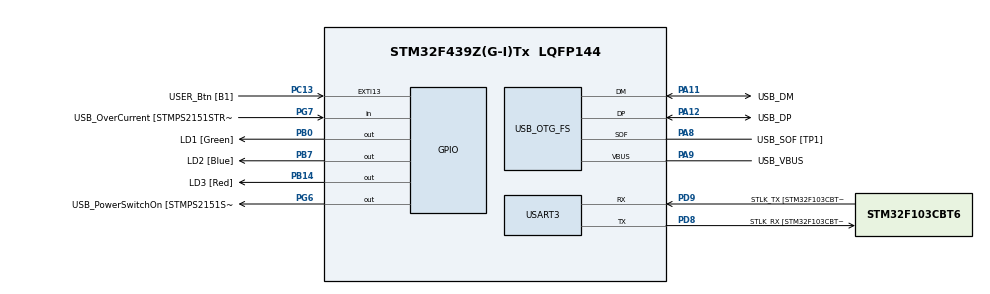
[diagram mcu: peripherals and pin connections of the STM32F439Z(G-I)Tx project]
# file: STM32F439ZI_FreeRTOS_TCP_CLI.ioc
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Mcu.Family=STM32F4
Mcu.Name=STM32F439Z(G-I)Tx
Mcu.Package=LQFP144
NVIC.PriorityGroup=NVIC_PRIORITYGROUP_4
NVIC.TIM6_DAC_IRQn=true\:15\:0\:false\:false\:true\:false\:true\:true
NVIC.TIM7_IRQn=true\:5\:0\:true\:false\:true\:true\:true\:true
NVIC.TimeBase=TIM6_DAC_IRQn
NVIC.TimeBaseIP=TIM6
PA1.GPIO_Label=RMII_REF_CLK [LAN8742A-CZ-TR_REFCLK0]
PA1.Signal=ETH_REF_CLK
PA10.GPIO_Label=USB_ID
PA10.Signal=USB_OTG_FS_ID
PA11.GPIO_Label=USB_DM
PA11.Mode=Device_Only
PA11.Signal=USB_OTG_FS_DM
PA12.GPIO_Label=USB_DP
PA12.Mode=Device_Only
PA12.Signal=USB_OTG_FS_DP
PA13.GPIO_Label=TMS
PA13.Mode=Serial_Wire
PA13.Signal=SYS_JTMS-SWDIO
PA14.GPIO_Label=TCK
PA14.Mode=Serial_Wire
PA14.Signal=SYS_JTCK-SWCLK
PA2.GPIO_Label=RMII_MDIO [LAN8742A-CZ-TR_MDIO]
PA2.Signal=ETH_MDIO
PA7.GPIO_Label=RMII_CRS_DV [LAN8742A-CZ-TR_CRS_DV]
PA7.Signal=ETH_CRS_DV
PA8.GPIO_Label=USB_SOF [TP1]
PA8.Mode=Activate_SOF_FS
PA8.Signal=USB_OTG_FS_SOF
PA9.GPIO_Label=USB_VBUS
PA9.Mode=Activate_VBUS
PA9.Signal=USB_OTG_FS_VBUS
PB0.GPIO_Label=LD1 [Green]
PB0.Signal=GPIO_Output
PB13.GPIO_Label=RMII_TXD1 [LAN8742A-CZ-TR_TXD1]
PB13.Signal=ETH_TXD1
PB14.GPIO_Label=LD3 [Red]
PB14.Signal=GPIO_Output
PB7.GPIO_Label=LD2 [Blue]
PB7.Signal=GPIO_Output
PC1.GPIO_Label=RMII_MDC [LAN8742A-CZ-TR_MDC]
PC1.Signal=ETH_MDC
PC13.GPIO_Label=USER_Btn [B1]
PC13.Signal=GPXTI13
PC14/OSC32_IN.Mode=LSE-External-Oscillator
PC14/OSC32_IN.Signal=RCC_OSC32_IN
PC15/OSC32_OUT.Mode=LSE-External-Oscillator
PC15/OSC32_OUT.Signal=RCC_OSC32_OUT
PC4.GPIO_Label=RMII_RXD0 [LAN8742A-CZ-TR_RXD0]
PC4.Signal=ETH_RXD0
PC5.GPIO_Label=RMII_RXD1 [LAN8742A-CZ-TR_RXD1]
PC5.Signal=ETH_RXD1
PD8.GPIO_Label=STLK_RX [STM32F103CBT6_PA3]
PD8.Mode=Asynchronous
PD8.Signal=USART3_TX
PD9.GPIO_Label=STLK_TX [STM32F103CBT6_PA2]
PD9.Mode=Asynchronous
PD9.Signal=USART3_RX
PG11.GPIO_Label=RMII_TX_EN [LAN8742A-CZ-TR_TXEN]
PG11.Signal=ETH_TX_EN
PG13.GPIO_Label=RMII_TXD0 [LAN8742A-CZ-TR_TXD0]
PG13.Signal=ETH_TXD0
PG6.GPIO_Label=USB_PowerSwitchOn [STMPS2151STR_EN]
PG6.Signal=GPIO_Output
PG7.GPIO_Label=USB_OverCurrent [STMPS2151STR_FAULT]
PG7.Signal=GPIO_Input
PH0/OSC_IN.GPIO_Label=MCO [STM32F103CBT6_PA8]
PH0/OSC_IN.Mode=HSE-External-Clock-Source
PH0/OSC_IN.Signal=RCC_OSC_IN
PH1/OSC_OUT.Mode=HSE-External-Clock-Source
PH1/OSC_OUT.Signal=RCC_OSC_OUT
ProjectManager.HeapSize=0x200
ProjectManager.StackSize=0x400
ProjectManager.TargetToolchain=STM32CubeIDE
RCC.48MHZClocksFreq_Value=48000000
RCC.AHBFreq_Value=72000000
RCC.APB1CLKDivider=RCC_HCLK_DIV2
RCC.APB1Freq_Value=36000000
RCC.APB1TimFreq_Value=72000000
RCC.APB2Freq_Value=72000000
RCC.APB2TimFreq_Value=72000000
RCC.CortexFreq_Value=72000000
RCC.HCLKFreq_Value=72000000
RCC.HSE_VALUE=8000000
RCC.HSI_VALUE=16000000
RCC.PLLM=4
RCC.PLLMUL=RCC_PLL_MUL9
RCC.PLLN=72
RCC.PLLQ=3
RCC.PRESCALERUSB=RCC_USBCLKSOURCE_PLL_DIV1_5
RCC.SYSCLKFreq_VALUE=72000000
RCC.SYSCLKSource=RCC_SYSCLKSOURCE_PLLCLK
RCC.SYSCLKSourceVirtual=RCC_SYSCLKSOURCE_PLLCLK
RCC.USBFreq_Value=48000000
RCC.VCOOutputFreq_Value=144000000
TIM7.Period=100 - 1
TIM7.Prescaler=72 - 1
USART3.VirtualMode=VM_ASYNC
USB_OTG_FS.VirtualMode=Device_Only
VP_RNG_VS_RNG.Mode=RNG_Activate
VP_SYS_VS_tim6.Mode=TIM6
VP_TIM7_VS_ClockSourceINT.Mode=Enable_Timer
board=NUCLEO-F439ZI

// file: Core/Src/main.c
/* USER CODE BEGIN Header */
/**
  ******************************************************************************
  * @file           : main.c
  * @brief          : Main program body
  ******************************************************************************
  * @attention
  *
  * Copyright (c) 2023 STMicroelectronics.
  * All rights reserved.
  *
  * This software is licensed under terms that can be found in the LICENSE file
  * in the root directory of this software component.
  * If no LICENSE file comes with this software, it is provided AS-IS.
  *
  ******************************************************************************
  */
/* USER CODE END Header */
#include "main.h"
#include "string.h"

/* USER CODE BEGIN Includes */

#include "FreeRTOS.h"
#include "task.h"
#include "semphr.h"

#include "logging.h"

/* USER CODE END Includes */

/* USER CODE BEGIN PM */
#define LED_HW 		1

/* USER CODE END PM */

#if 0
ETH_TxPacketConfig TxConfig;
ETH_DMADescTypeDef  DMARxDscrTab[ETH_RX_DESC_CNT]; /* Ethernet Rx DMA Descriptors */
ETH_DMADescTypeDef  DMATxDscrTab[ETH_TX_DESC_CNT]; /* Ethernet Tx DMA Descriptors */

ETH_HandleTypeDef heth;
#endif

RNG_HandleTypeDef hrng;

TIM_HandleTypeDef htim7;

UART_HandleTypeDef huart3;

PCD_HandleTypeDef hpcd_USB_OTG_FS;

/* USER CODE BEGIN PV */

uint32_t ulGetTim7Tick()
{
	return 0;
}

#if LED_HW

/* Logging module configuration. */
#define mainLOGGING_TASK_STACK_SIZE    256
#define mainLOGGING_QUEUE_LENGTH       100

SemaphoreHandle_t xSemaphore1 = NULL;
SemaphoreHandle_t xSemaphore2 = NULL;
SemaphoreHandle_t xSemaphore3 = NULL;

void vToggleLED(SemaphoreHandle_t xSem, uint16_t pin, uint16_t taskId)
{

    if( xSem != NULL )
    {
        if( xSemaphoreTake( xSem, portMAX_DELAY ) == pdTRUE )
        {

        	configPRINTF(("Task %d in critical section [M1]. Priority: %d\r\n", taskId, uxTaskPriorityGet(NULL)));

          if( xSemaphoreTake( xSemaphore2, portMAX_DELAY ) == pdTRUE )
          {

            configPRINTF(("Task %d in critical section [M1, M2]. Priority: %d\r\n", taskId, uxTaskPriorityGet(NULL)));

            if( xSemaphoreTake( xSemaphore3, portMAX_DELAY ) == pdTRUE )
            {

              configPRINTF(("Task %d in critical section [M1, M2, M3]. Priority: %d\r\n", taskId, uxTaskPriorityGet(NULL)));

              HAL_GPIO_TogglePin(GPIOB, pin);
              HAL_Delay(200);

              xSemaphoreGive( xSemaphore3 );

              configPRINTF(("Task %d in critical section [M1, M2]. Priority: %d\r\n", taskId, uxTaskPriorityGet(NULL)));

            }

            xSemaphoreGive( xSemaphore2 );

            configPRINTF(("Task %d in critical section [M1]. Priority: %d\r\n", taskId, uxTaskPriorityGet(NULL)));

          }

          xSemaphoreGive( xSem );

          configPRINTF(("Task %d in outside critical section. Priority: %d\r\n", taskId, uxTaskPriorityGet(NULL)));

        }
        else
        {
            /* We could not obtain the semaphore and can therefore not access
               the shared resource safely. */
        }
    }
}

static void task_1_thread_fn(void *io_params) {

	configPRINTF(("Task 1 starting. Priority: %d\r\n", uxTaskPriorityGet(NULL)));

	while(1) {
		vToggleLED(xSemaphore1, GPIO_PIN_7, 1);
		vTaskDelay(20);
	}
}

static void task_2_thread_fn(void *io_params) {

	configPRINTF(("Task 2 starting. Priority: %d\r\n", uxTaskPriorityGet(NULL)));

	while(1) {
		vToggleLED(xSemaphore1, GPIO_PIN_14, 2);
		vTaskDelay(20);
	}
}

static void task_1_thread_fn_simple(void *io_params) {
	while(1) {
		HAL_GPIO_TogglePin(GPIOB, GPIO_PIN_7);
		vTaskDelay(100);
	}
}

static void task_2_thread_fn_simple(void *io_params) {
	while(1) {
		HAL_GPIO_TogglePin(GPIOB, GPIO_PIN_14);
		vTaskDelay(200);
	}
}
#endif

/* USER CODE END PV */

void SystemClock_Config(void);
static void MX_GPIO_Init(void);
static void MX_USART3_UART_Init(void);
static void MX_USB_OTG_FS_PCD_Init(void);
static void MX_RNG_Init(void);
static void MX_TIM7_Init(void);

int main(void)
{

  /* MCU Configuration--------------------------------------------------------*/

  /* Reset of all peripherals, Initializes the Flash interface and the Systick. */
  HAL_Init();

  /* Configure the system clock */
  SystemClock_Config();

  /* Initialize all configured peripherals */
  MX_GPIO_Init();
  //MX_ETH_Init();
  MX_USART3_UART_Init();
  MX_USB_OTG_FS_PCD_Init();
  MX_RNG_Init();
  MX_TIM7_Init();
  /* USER CODE BEGIN 2 */

#if LED_HW

  TaskHandle_t task_1_handle, task_2_handle;
  BaseType_t ret_status;

  ret_status = xLoggingTaskInitialize( mainLOGGING_TASK_STACK_SIZE,
                                 3,
                                 mainLOGGING_QUEUE_LENGTH );
  configASSERT( ret_status == pdPASS );

  xSemaphore1 = xSemaphoreCreateMutexICPP(3);
  xSemaphore2 = xSemaphoreCreateMutexICPP(5);
  xSemaphore3 = xSemaphoreCreateMutexICPP(4);

  ret_status = xTaskCreate(task_1_thread_fn, "Task_1", 200, "HW from 1", 2, &task_1_handle);
  configASSERT(ret_status == pdPASS);

  ret_status = xTaskCreate(task_2_thread_fn, "Task_2", 200, "HW from 2", 2, &task_2_handle);
  configASSERT(ret_status == pdPASS);

  vTaskStartScheduler();

#elif TCP_CLI

#endif

  /* USER CODE END 2 */

  /* Infinite loop */
  while (1)
  {

  }
}

void vPrintStringToUart( const char * str )
{
    HAL_UART_Transmit( &( huart3 ), ( const uint8_t * ) str, strlen( str ), 1000 );
}

void SystemClock_Config(void)
{
  RCC_OscInitTypeDef RCC_OscInitStruct = {0};
  RCC_ClkInitTypeDef RCC_ClkInitStruct = {0};

  /** Configure the main internal regulator output voltage
  */
  __HAL_RCC_PWR_CLK_ENABLE();
  __HAL_PWR_VOLTAGESCALING_CONFIG(PWR_REGULATOR_VOLTAGE_SCALE1);

  /** Initializes the RCC Oscillators according to the specified parameters
  * in the RCC_OscInitTypeDef structure.
  */
  RCC_OscInitStruct.OscillatorType = RCC_OSCILLATORTYPE_HSE;
  RCC_OscInitStruct.HSEState = RCC_HSE_BYPASS;
  RCC_OscInitStruct.PLL.PLLState = RCC_PLL_ON;
  RCC_OscInitStruct.PLL.PLLSource = RCC_PLLSOURCE_HSE;
  RCC_OscInitStruct.PLL.PLLM = 4;
  RCC_OscInitStruct.PLL.PLLN = 168;
  RCC_OscInitStruct.PLL.PLLP = RCC_PLLP_DIV2;
  RCC_OscInitStruct.PLL.PLLQ = 7;
  if (HAL_RCC_OscConfig(&RCC_OscInitStruct) != HAL_OK)
  {
    Error_Handler();
  }

  /** Initializes the CPU, AHB and APB buses clocks
  */
  RCC_ClkInitStruct.ClockType = RCC_CLOCKTYPE_HCLK|RCC_CLOCKTYPE_SYSCLK
                              |RCC_CLOCKTYPE_PCLK1|RCC_CLOCKTYPE_PCLK2;
  RCC_ClkInitStruct.SYSCLKSource = RCC_SYSCLKSOURCE_PLLCLK;
  RCC_ClkInitStruct.AHBCLKDivider = RCC_SYSCLK_DIV1;
  RCC_ClkInitStruct.APB1CLKDivider = RCC_HCLK_DIV4;
  RCC_ClkInitStruct.APB2CLKDivider = RCC_HCLK_DIV2;

  if (HAL_RCC_ClockConfig(&RCC_ClkInitStruct, FLASH_LATENCY_5) != HAL_OK)
  {
    Error_Handler();
  }
}

#if 0
static void MX_ETH_Init(void)
{

   static uint8_t MACAddr[6];

  heth.Instance = ETH;
  MACAddr[0] = 0x00;
  MACAddr[1] = 0x80;
  MACAddr[2] = 0xE1;
  MACAddr[3] = 0x00;
  MACAddr[4] = 0x00;
  MACAddr[5] = 0x00;
  heth.Init.MACAddr = &MACAddr[0];
  heth.Init.MediaInterface = HAL_ETH_RMII_MODE;
  heth.Init.TxDesc = DMATxDscrTab;
  heth.Init.RxDesc = DMARxDscrTab;
  heth.Init.RxBuffLen = 1524;

  if (HAL_ETH_Init(&heth) != HAL_OK)
  {
    Error_Handler();
  }

  memset(&TxConfig, 0 , sizeof(ETH_TxPacketConfig));
  TxConfig.Attributes = ETH_TX_PACKETS_FEATURES_CSUM | ETH_TX_PACKETS_FEATURES_CRCPAD;
  TxConfig.ChecksumCtrl = ETH_CHECKSUM_IPHDR_PAYLOAD_INSERT_PHDR_CALC;
  TxConfig.CRCPadCtrl = ETH_CRC_PAD_INSERT;

}
#endif

static void MX_RNG_Init(void)
{

  hrng.Instance = RNG;
  if (HAL_RNG_Init(&hrng) != HAL_OK)
  {
    Error_Handler();
  }

}

static void MX_TIM7_Init(void)
{

  TIM_MasterConfigTypeDef sMasterConfig = {0};

  htim7.Instance = TIM7;
  htim7.Init.Prescaler = 42;
  htim7.Init.CounterMode = TIM_COUNTERMODE_UP;
  htim7.Init.Period = 99;
  htim7.Init.AutoReloadPreload = TIM_AUTORELOAD_PRELOAD_DISABLE;
  if (HAL_TIM_Base_Init(&htim7) != HAL_OK)
  {
    Error_Handler();
  }
  sMasterConfig.MasterOutputTrigger = TIM_TRGO_RESET;
  sMasterConfig.MasterSlaveMode = TIM_MASTERSLAVEMODE_DISABLE;
  if (HAL_TIMEx_MasterConfigSynchronization(&htim7, &sMasterConfig) != HAL_OK)
  {
    Error_Handler();
  }

}

static void MX_USART3_UART_Init(void)
{

  huart3.Instance = USART3;
  huart3.Init.BaudRate = 115200;
  huart3.Init.WordLength = UART_WORDLENGTH_8B;
  huart3.Init.StopBits = UART_STOPBITS_1;
  huart3.Init.Parity = UART_PARITY_NONE;
  huart3.Init.Mode = UART_MODE_TX_RX;
  huart3.Init.HwFlowCtl = UART_HWCONTROL_NONE;
  huart3.Init.OverSampling = UART_OVERSAMPLING_16;
  if (HAL_UART_Init(&huart3) != HAL_OK)
  {
    Error_Handler();
  }

}

static void MX_USB_OTG_FS_PCD_Init(void)
{

  hpcd_USB_OTG_FS.Instance = USB_OTG_FS;
  hpcd_USB_OTG_FS.Init.dev_endpoints = 4;
  hpcd_USB_OTG_FS.Init.speed = PCD_SPEED_FULL;
  hpcd_USB_OTG_FS.Init.dma_enable = DISABLE;
  hpcd_USB_OTG_FS.Init.phy_itface = PCD_PHY_EMBEDDED;
  hpcd_USB_OTG_FS.Init.Sof_enable = ENABLE;
  hpcd_USB_OTG_FS.Init.low_power_enable = DISABLE;
  hpcd_USB_OTG_FS.Init.lpm_enable = DISABLE;
  hpcd_USB_OTG_FS.Init.vbus_sensing_enable = ENABLE;
  hpcd_USB_OTG_FS.Init.use_dedicated_ep1 = DISABLE;
  if (HAL_PCD_Init(&hpcd_USB_OTG_FS) != HAL_OK)
  {
    Error_Handler();
  }

}

static void MX_GPIO_Init(void)
{
  GPIO_InitTypeDef GPIO_InitStruct = {0};

  /* GPIO Ports Clock Enable */
  __HAL_RCC_GPIOC_CLK_ENABLE();
  __HAL_RCC_GPIOH_CLK_ENABLE();
  __HAL_RCC_GPIOA_CLK_ENABLE();
  __HAL_RCC_GPIOB_CLK_ENABLE();
  __HAL_RCC_GPIOD_CLK_ENABLE();
  __HAL_RCC_GPIOG_CLK_ENABLE();

  /*Configure GPIO pin Output Level */
  HAL_GPIO_WritePin(GPIOB, LD1_Pin|LD3_Pin|LD2_Pin, GPIO_PIN_RESET);

  /*Configure GPIO pin Output Level */
  HAL_GPIO_WritePin(USB_PowerSwitchOn_GPIO_Port, USB_PowerSwitchOn_Pin, GPIO_PIN_RESET);

  /*Configure GPIO pin : USER_Btn_Pin */
  GPIO_InitStruct.Pin = USER_Btn_Pin;
  GPIO_InitStruct.Mode = GPIO_MODE_IT_RISING;
  GPIO_InitStruct.Pull = GPIO_NOPULL;
  HAL_GPIO_Init(USER_Btn_GPIO_Port, &GPIO_InitStruct);

  /*Configure GPIO pins : LD1_Pin LD3_Pin LD2_Pin */
  GPIO_InitStruct.Pin = LD1_Pin|LD3_Pin|LD2_Pin;
  GPIO_InitStruct.Mode = GPIO_MODE_OUTPUT_PP;
  GPIO_InitStruct.Pull = GPIO_NOPULL;
  GPIO_InitStruct.Speed = GPIO_SPEED_FREQ_LOW;
  HAL_GPIO_Init(GPIOB, &GPIO_InitStruct);

  /*Configure GPIO pin : USB_PowerSwitchOn_Pin */
  GPIO_InitStruct.Pin = USB_PowerSwitchOn_Pin;
  GPIO_InitStruct.Mode = GPIO_MODE_OUTPUT_PP;
  GPIO_InitStruct.Pull = GPIO_NOPULL;
  GPIO_InitStruct.Speed = GPIO_SPEED_FREQ_LOW;
  HAL_GPIO_Init(USB_PowerSwitchOn_GPIO_Port, &GPIO_InitStruct);

  /*Configure GPIO pin : USB_OverCurrent_Pin */
  GPIO_InitStruct.Pin = USB_OverCurrent_Pin;
  GPIO_InitStruct.Mode = GPIO_MODE_INPUT;
  GPIO_InitStruct.Pull = GPIO_NOPULL;
  HAL_GPIO_Init(USB_OverCurrent_GPIO_Port, &GPIO_InitStruct);

}

/* USER CODE BEGIN 4 */

/*-----------------------------------------------------------*/

void vApplicationStackOverflowHook( TaskHandle_t pxTask, char *pcTaskName )
{
    /* If configCHECK_FOR_STACK_OVERFLOW is set to either 1 or 2 then this
     * function will automatically get called if a task overflows its stack. */
    ( void ) pxTask;
    ( void ) pcTaskName;
    for( ;; );
}
/*-----------------------------------------------------------*/

void vApplicationMallocFailedHook( void )
{
    /* If configUSE_MALLOC_FAILED_HOOK is set to 1 then this function will
     * be called automatically if a call to pvPortMalloc() fails.  pvPortMalloc()
     * is called automatically when a task, queue or semaphore is created. */
    for( ;; );
}
/*-----------------------------------------------------------*/

/* configUSE_STATIC_ALLOCATION is set to 1, so the application must provide an
 * implementation of vApplicationGetIdleTaskMemory() to provide the memory that is
 * used by the Idle task. */
void vApplicationGetIdleTaskMemory( StaticTask_t **ppxIdleTaskTCBBuffer, StackType_t **ppxIdleTaskStackBuffer, uint32_t *pulIdleTaskStackSize )
{
/* If the buffers to be provided to the Idle task are declared inside this
 * function then they must be declared static - otherwise they will be allocated on
 * the stack and so not exists after this function exits. */
static StaticTask_t xIdleTaskTCB;
static StackType_t uxIdleTaskStack[ configMINIMAL_STACK_SIZE ];

    /* Pass out a pointer to the StaticTask_t structure in which the Idle task's
     * state will be stored. */
    *ppxIdleTaskTCBBuffer = &xIdleTaskTCB;

    /* Pass out the array that will be used as the Idle task's stack. */
    *ppxIdleTaskStackBuffer = uxIdleTaskStack;

    /* Pass out the size of the array pointed to by *ppxIdleTaskStackBuffer.
     * Note that, as the array is necessarily of type StackType_t,
     * configMINIMAL_STACK_SIZE is specified in words, not bytes. */
    *pulIdleTaskStackSize = configMINIMAL_STACK_SIZE;
}
/*-----------------------------------------------------------*/

/* configUSE_STATIC_ALLOCATION and configUSE_TIMERS are both set to 1, so the
 * application must provide an implementation of vApplicationGetTimerTaskMemory()
 * to provide the memory that is used by the Timer service task. */
void vApplicationGetTimerTaskMemory( StaticTask_t **ppxTimerTaskTCBBuffer, StackType_t **ppxTimerTaskStackBuffer, uint32_t *pulTimerTaskStackSize )
{
/* If the buffers to be provided to the Timer task are declared inside this
 * function then they must be declared static - otherwise they will be allocated on
 * the stack and so not exists after this function exits. */
static StaticTask_t xTimerTaskTCB;
static StackType_t uxTimerTaskStack[ configTIMER_TASK_STACK_DEPTH ];

    /* Pass out a pointer to the StaticTask_t structure in which the Timer
     * task's state will be stored. */
    *ppxTimerTaskTCBBuffer = &xTimerTaskTCB;

    /* Pass out the array that will be used as the Timer task's stack. */
    *ppxTimerTaskStackBuffer = uxTimerTaskStack;

    /* Pass out the size of the array pointed to by *ppxTimerTaskStackBuffer.
     * Note that, as the array is necessarily of type StackType_t,
     * configMINIMAL_STACK_SIZE is specified in words, not bytes. */
    *pulTimerTaskStackSize = configTIMER_TASK_STACK_DEPTH;
}
/*-----------------------------------------------------------*/

/* USER CODE END 4 */

void HAL_TIM_PeriodElapsedCallback(TIM_HandleTypeDef *htim)
{
  if (htim->Instance == TIM6) {
    HAL_IncTick();
  }
}

void Error_Handler(void)
{
  __disable_irq();
  while (1)
  {
  }
}
